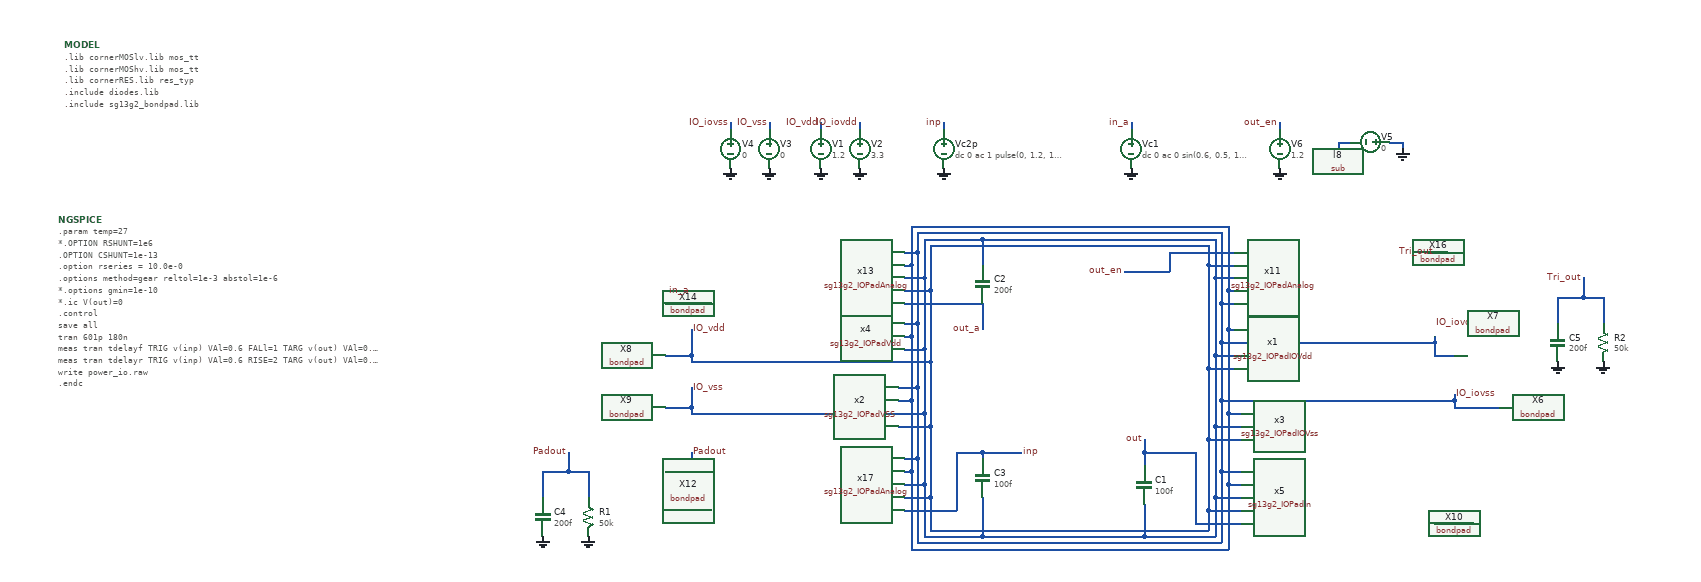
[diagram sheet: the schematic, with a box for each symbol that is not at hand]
v {xschem version=3.4.8RC file_version=1.3}
G {}
K {}
V {}
S {}
F {}
E {}
B 2 -30 260 770 660 {flags=graph
y1=-0.014
y2=1.3
ypos1=0
ypos2=2
divy=5
subdivy=1
unity=1
x1=-5.537876e-09
x2=1.0521964e-07
subdivx=1
xlabmag=1.0
ylabmag=1.0
dataset=-1
unitx=1
logx=0
logy=0
color="7 6 4 8"
node="inp
out
out_a
in_a"
linewidth_mult=0.5
divx=20
}
B 2 -840 260 -40 660 {flags=graph
y1=-0.011
y2=3.3
ypos1=0
ypos2=2
divy=5
subdivy=1
unity=1
x1=-5.537876e-09
x2=1.0521964e-07
subdivx=1
xlabmag=1.0
ylabmag=1.0
dataset=-1
unitx=1
logx=0
logy=0
color="6 21 11"
node="inp
Padout
tri_out"
linewidth_mult=0.5
divx=20
hilight_wave=0}
N -410 -440 -410 -430 {
lab=IO_vdd}
N -350 -440 -350 -430 {
lab=IO_iovdd}
N -490 -440 -490 -430 {
lab=IO_vss}
N -550 -440 -550 -430 {
lab=IO_iovss}
N -220 -440 -220 -430 {
lab=inp}
N 570 180 600 180 {lab=inp}
N 570 170 570 180 {lab=inp}
N 540 180 570 180 {lab=inp}
N -240 -250 190 -250 {lab=IO_vdd}
N 90 200 200 200 {lab=IO_vss}
N -160 -260 200 -260 {lab=IO_vss}
N -260 -270 210 -270 {lab=IO_iovss}
N -260 210 210 210 {lab=IO_iovss}
N -270 220 220 220 {lab=#net1}
N -270 -280 220 -280 {lab=#net1}
N 90 70 90 90 {lab=out}
N 540 -100 540 -80 {lab=IO_iovss}
N -610 -30 -610 0 {lab=IO_vss}
N -610 -120 -610 -80 {lab=IO_vdd}
N -250 120 -250 200 {lab=IO_vss}
N -610 10 -250 10 {lab=IO_vss}
N -650 0 -610 0 {lab=IO_vss}
N -650 -80 -610 -80 {lab=IO_vdd}
N -650 100 -610 100 {lab=Padout}
N -160 70 -100 70 {lab=inp}
N -240 190 190 190 {lab=IO_vdd}
N 90 150 90 200 {lab=IO_vss}
N -160 200 90 200 {lab=IO_vss}
N -250 -90 -250 10 {lab=IO_vss}
N -260 80 -260 210 {lab=IO_iovss}
N -160 -260 -160 -220 {lab=IO_vss}
N -250 -260 -160 -260 {lab=IO_vss}
N -610 -180 -610 -160 {lab=in_a}
N -650 -160 -610 -160 {lab=in_a}
N 70 -440 70 -430 {
lab=in_a}
N -160 -160 -160 -120 {lab=out_a}
N -240 140 -240 190 {lab=IO_vdd}
N 470 -410 490 -410 {lab=GND}
N 490 -410 490 -400 {lab=GND}
N 390 -410 410 -410 {lab=sub!}
N 390 -410 390 -400 {lab=sub!}
N -160 140 -160 200 {lab=IO_vss}
N -250 200 -160 200 {lab=IO_vss}
N -610 70 -610 100 {lab=Padout}
N -160 70 -160 80 {lab=inp}
N 300 -440 300 -430 {
lab=out_en}
N -200 70 -160 70 {lab=inp}
N 200 140 200 200 {lab=IO_vss}
N 730 -170 730 -130 {lab=Tri_out}
N 770 -170 800 -170 {lab=Tri_out}
N 800 -170 800 -130 {lab=Tri_out}
N 770 -200 770 -170 {lab=Tri_out}
N 730 -170 770 -170 {lab=Tri_out}
N 190 160 190 190 {lab=IO_vdd}
N -840 100 -840 140 {lab=Padout}
N -800 100 -770 100 {lab=Padout}
N -770 100 -770 140 {lab=Padout}
N -800 70 -800 100 {lab=Padout}
N -840 100 -800 100 {lab=Padout}
N -270 100 -270 220 {lab=#net1}
N -610 -160 -580 -160 {lab=in_a}
N -280 -160 -160 -160 {lab=out_a}
N -280 -180 -240 -180 {lab=IO_vdd}
N -240 -250 -240 -180 {lab=IO_vdd}
N -280 -200 -250 -200 {lab=IO_vss}
N -250 -260 -250 -200 {lab=IO_vss}
N -280 -240 -260 -240 {lab=IO_iovss}
N -260 -270 -260 -240 {lab=IO_iovss}
N -280 -220 -270 -220 {lab=#net1}
N -270 -280 -270 -220 {lab=#net1}
N -610 -80 -610 -70 {lab=IO_vdd}
N -610 -70 -240 -70 {lab=IO_vdd}
N -240 -180 -240 -70 {lab=IO_vdd}
N -280 -90 -250 -90 {lab=IO_vss}
N -250 -200 -250 -90 {lab=IO_vss}
N -280 -110 -270 -110 {lab=#net1}
N -270 -220 -270 -110 {lab=#net1}
N -280 -130 -260 -130 {lab=IO_iovss}
N -260 -240 -260 -130 {lab=IO_iovss}
N -610 0 -610 10 {lab=IO_vss}
N -290 30 -240 30 {lab=IO_vdd}
N -240 -70 -240 30 {lab=IO_vdd}
N -290 -10 -270 -10 {lab=#net1}
N -270 -110 -270 -10 {lab=#net1}
N -290 -30 -260 -30 {lab=IO_iovss}
N -260 -130 -260 -30 {lab=IO_iovss}
N -610 100 -610 160 {lab=Padout}
N -610 160 -580 160 {lab=Padout}
N -280 160 -200 160 {lab=inp}
N -200 70 -200 160 {lab=inp}
N -280 140 -240 140 {lab=IO_vdd}
N -240 30 -240 140 {lab=IO_vdd}
N -280 120 -250 120 {lab=IO_vss}
N -250 10 -250 120 {lab=IO_vss}
N -280 100 -270 100 {lab=#net1}
N -270 -10 -270 100 {lab=#net1}
N -280 80 -260 80 {lab=IO_iovss}
N -260 -30 -260 80 {lab=IO_iovss}
N 530 -240 560 -240 {lab=Tri_out}
N 130 -240 230 -240 {lab=out_en}
N 130 -240 130 -210 {lab=out_en}
N 60 -210 130 -210 {lab=out_en}
N 190 -220 230 -220 {lab=IO_vdd}
N 190 -250 190 -220 {lab=IO_vdd}
N 200 -200 230 -200 {lab=IO_vss}
N 200 -260 200 -200 {lab=IO_vss}
N 220 -180 230 -180 {lab=#net1}
N 220 -280 220 -180 {lab=#net1}
N 210 -160 230 -160 {lab=IO_iovss}
N 210 -270 210 -160 {lab=IO_iovss}
N 170 180 240 180 {lab=out}
N 170 70 170 180 {lab=out}
N 90 70 170 70 {lab=out}
N 90 50 90 70 {lab=out}
N 220 120 220 220 {lab=#net1}
N 210 100 210 210 {lab=IO_iovss}
N 210 100 240 100 {lab=IO_iovss}
N 210 -10 210 100 {lab=IO_iovss}
N 220 120 240 120 {lab=#net1}
N 220 10 220 120 {lab=#net1}
N 200 140 240 140 {lab=IO_vss}
N 200 30 200 140 {lab=IO_vss}
N 190 160 240 160 {lab=IO_vdd}
N 190 50 190 160 {lab=IO_vdd}
N 570 -0 640 0 {lab=IO_iovss}
N 570 -10 570 -0 {lab=IO_iovss}
N 570 -20 570 -10 {lab=IO_iovss}
N 210 -10 570 -10 {lab=IO_iovss}
N 210 -100 210 -10 {lab=IO_iovss}
N 220 10 240 10 {lab=#net1}
N 220 -120 220 10 {lab=#net1}
N 200 30 240 30 {lab=IO_vss}
N 200 -80 200 30 {lab=IO_vss}
N 190 50 240 50 {lab=IO_vdd}
N 190 -60 190 50 {lab=IO_vdd}
N 540 -80 570 -80 {lab=IO_iovss}
N 210 -100 540 -100 {lab=IO_iovss}
N 210 -160 210 -100 {lab=IO_iovss}
N 540 -110 540 -100 {lab=IO_iovss}
N 220 -120 230 -120 {lab=#net1}
N 220 -180 220 -120 {lab=#net1}
N 200 -80 230 -80 {lab=IO_vss}
N 200 -200 200 -80 {lab=IO_vss}
N 190 -60 230 -60 {lab=IO_vdd}
N 190 -220 190 -60 {lab=IO_vdd}
C {vsource.sym} -410 -400 0 0 {name=V1 value=1.2}
C {gnd.sym} -410 -370 0 0 {name=l3 lab=GND}
C {lab_pin.sym} -410 -440 1 0 {name=p7 sig_type=std_logic lab=IO_vdd}
C {vsource.sym} -350 -400 0 0 {name=V2 value=3.3
}
C {gnd.sym} -350 -370 0 0 {name=l4 lab=GND}
C {lab_pin.sym} -350 -440 1 0 {name=p8 sig_type=std_logic lab=IO_iovdd}
C {vsource.sym} -490 -400 0 0 {name=V3 value=0 savecurrent=false}
C {gnd.sym} -490 -370 0 0 {name=l5 lab=GND}
C {lab_pin.sym} -490 -440 1 0 {name=p9 sig_type=std_logic lab=IO_vss}
C {vsource.sym} -550 -400 0 0 {name=V4 value=0 savecurrent=false}
C {gnd.sym} -550 -370 0 0 {name=l6 lab=GND}
C {lab_pin.sym} -550 -440 1 0 {name=p10 sig_type=std_logic lab=IO_iovss}
C {vsource.sym} -220 -400 0 0 {name=Vc2p value="dc 0 ac 1 pulse(0, 1.2, 1n, 1n, 1n, 50n, 100n ) "}
C {gnd.sym} -220 -370 0 0 {name=l9 lab=GND}
C {lab_pin.sym} -220 -440 1 0 {name=p15 sig_type=std_logic lab=inp}
C {devices/code_shown.sym} -1580 -560 0 0 {name=MODEL only_toplevel=true
format="tcleval( @value )"
value="
.lib cornerMOSlv.lib mos_tt
.lib cornerMOShv.lib mos_tt
.lib cornerRES.lib res_typ
.include diodes.lib
.include sg13g2_bondpad.lib
"}
C {devices/code_shown.sym} -1590 -290 0 0 {name=NGSPICE only_toplevel=true 
value="
.param temp=27
*.OPTION RSHUNT=1e6
.OPTION CSHUNT=1e-13
.option rseries = 10.0e-0
.options method=gear reltol=1e-3 abstol=1e-6
*.options gmin=1e-10
*.ic V(out)=0

.control
save all 
tran  601p 180n 
meas tran tdelayf TRIG v(inp) VAl=0.6 FALl=1 TARG v(out) VAl=0.6 FALL=1
meas tran tdelayr TRIG v(inp) VAl=0.6 RISE=2 TARG v(out) VAl=0.6 RISE=2
write power_io.raw


.endc
"}
C {lab_pin.sym} 540 -130 2 0 {name=p3 sig_type=std_logic lab=IO_iovdd}
C {lab_pin.sym} 570 -20 2 0 {name=p4 sig_type=std_logic lab=IO_iovss}
C {lab_pin.sym} -610 -120 0 1 {name=p5 sig_type=std_logic lab=IO_vdd}
C {lab_pin.sym} -610 -30 2 0 {name=p6 sig_type=std_logic lab=IO_vss}
C {sg13g2_IOPadIOVdd.sym} 380 -80 2 0 {name=x1}
C {sg13g2_IOPadIOVss.sym} 390 30 2 0 {name=x3}
C {sg13g2_IOPadVSS.sym} -430 10 2 1 {name=x2}
C {sg13g2_IOPadVdd.sym} -430 -90 2 1 {name=x4}
C {sg13g2_IOPadIn.sym} 390 140 2 0 {name=x5}
C {capa.sym} 90 120 0 0 {name=C1
m=1
value=100f
footprint=1206
device="ceramic capacitor"}
C {lab_pin.sym} 90 50 0 0 {name=p17 sig_type=std_logic lab=out}
C {lab_pin.sym} 570 170 1 0 {name=p2 sig_type=std_logic lab=inp}
C {sg13g2_pr/bondpad.sym} 650 0 1 0 {name=X6
model=bondpad
spiceprefix=X
size=80u
shape=0
padtype=0
}
C {sg13g2_pr/bondpad.sym} 610 -80 1 0 {name=X7
model=bondpad
spiceprefix=X
size=80u
shape=0
padtype=0
}
C {sg13g2_pr/bondpad.sym} -690 -80 3 1 {name=X8
model=bondpad
spiceprefix=X
size=80u
shape=0
padtype=0
}
C {sg13g2_pr/bondpad.sym} -690 0 3 1 {name=X9
model=bondpad
spiceprefix=X
size=80u
shape=0
padtype=0
}
C {sg13g2_pr/bondpad.sym} 630 180 1 0 {name=X10
model=bondpad
spiceprefix=X
size=80u
shape=0
padtype=0
}
C {devices/launcher.sym} -810 690 0 0 {name=h5
descr="load waves Ctrl + left click" 
tclcommand="xschem raw_read $netlist_dir/power_io.raw tran"
}
C {sg13g2_pr/bondpad.sym} -690 100 3 1 {name=X12
model=bondpad
spiceprefix=X
size=80u
shape=0
padtype=0
}
C {sg13g2_IOPadAnalog.sym} -430 -200 2 1 {name=x13}
C {capa.sym} -160 -190 2 0 {name=C2
m=1
value=200f
footprint=1206
device="ceramic capacitor"}
C {sg13g2_pr/bondpad.sym} -690 -160 3 1 {name=X14
model=bondpad
spiceprefix=X
size=80u
shape=0
padtype=0
}
C {vsource.sym} 70 -400 0 0 {name=Vc1 value="dc 0 ac 0 sin(0.6, 0.5, 100meg, 1n) "}
C {gnd.sym} 70 -370 0 0 {name=l7 lab=GND}
C {lab_pin.sym} 70 -440 1 0 {name=p11 sig_type=std_logic lab=in_a}
C {lab_pin.sym} -160 -120 0 0 {name=p12 sig_type=std_logic lab=out_a}
C {lab_pin.sym} -610 -180 1 0 {name=p1 sig_type=std_logic lab=in_a}
C {sg13g2_pr/sub.sym} 390 -400 0 0 {name=l8 lab=sub!}
C {gnd.sym} 490 -400 0 0 {name=l11 lab=GND}
C {vsource.sym} 440 -410 1 0 {name=V5 value=0 savecurrent=false}
C {capa.sym} -160 110 0 0 {name=C3
m=1
value=100f
footprint=1206
device="ceramic capacitor"}
C {lab_pin.sym} -100 70 2 0 {name=p13 sig_type=std_logic lab=inp}
C {lab_pin.sym} -610 70 0 1 {name=p14 sig_type=std_logic lab=Padout}
C {vsource.sym} 300 -400 0 0 {name=V6 value=1.2}
C {gnd.sym} 300 -370 0 0 {name=l1 lab=GND}
C {lab_pin.sym} 300 -440 1 0 {name=p18 sig_type=std_logic lab=out_en}
C {lab_pin.sym} 60 -210 0 0 {name=p19 sig_type=std_logic lab=out_en}
C {sg13g2_pr/bondpad.sym} 600 -240 1 0 {name=X16
model=bondpad
spiceprefix=X
size=80u
shape=0
padtype=0
}
C {lab_pin.sym} 540 -240 1 0 {name=p20 sig_type=std_logic lab=Tri_out}
C {capa.sym} 730 -100 2 0 {name=C5
m=1
value=200f
footprint=1206
device="ceramic capacitor"}
C {res.sym} 800 -100 0 0 {name=R2
value=50k
footprint=1206
device=resistor
m=1}
C {gnd.sym} 730 -70 0 0 {name=l13 lab=GND}
C {gnd.sym} 800 -70 0 0 {name=l14 lab=GND}
C {lab_pin.sym} 770 -200 1 0 {name=p22 sig_type=std_logic lab=Tri_out}
C {capa.sym} -840 170 2 0 {name=C4
m=1
value=200f
footprint=1206
device="ceramic capacitor"}
C {res.sym} -770 170 0 0 {name=R1
value=50k
footprint=1206
device=resistor
m=1}
C {gnd.sym} -840 200 0 0 {name=l2 lab=GND}
C {gnd.sym} -770 200 0 0 {name=l12 lab=GND}
C {lab_pin.sym} -800 70 1 0 {name=p21 sig_type=std_logic lab=Padout}
C {sg13g2_IOPadAnalog.sym} -430 120 2 1 {name=x17}
C {sg13g2_IOPadAnalog.sym} 380 -200 0 1 {name=x11}
